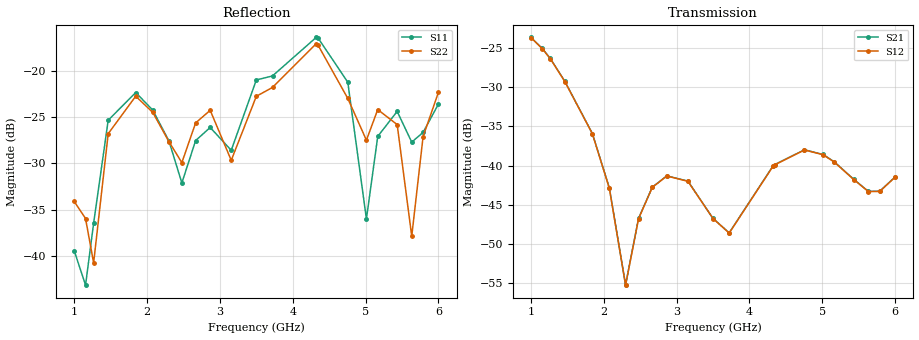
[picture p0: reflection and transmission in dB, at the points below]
!Agilent Technologies,E8364B,MY43040528,A.07.50.67
!Agilent E8364B: A.07.50.67
!Date: Sunday, March 01, 2026 20:46:33
!Correction: S11(Full 2 Port(1,2))
!S21(Full 2 Port(1,2))
!S12(Full 2 Port(1,2))
!S22(Full 2 Port(1,2))
!S2P File: Measurements: S11, S21, S12, S22:
# Hz S  dB  R 50
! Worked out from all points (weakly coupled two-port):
!   451 points, 1 GHz to 6 GHz, reference 50 ohm
!   highest |S21| = -23.64 dB at 1 GHz (marker M1); lowest = -55.2 dB at 2.3 GHz (marker M2)
!   lowest |S11| = -43.1 dB at 1.156 GHz (marker M3), VSWR 1.01, Z = 49.5 + j0.524 ohm
!   |S11| at or under -10 dB: start of sweep to end of sweep
!   |S22| runs from -40.8 to -16.9 dB; largest |S21 - S12| = 0.00017
!   S11 on the Smith chart (normalised r, x): 1 GHz: 1.01, +0.02; 4.322 GHz: 1.24, -0.24; 6 GHz: 0.99, -0.13
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1e9  -39.42 64.4  -23.64 148.8  -23.66 148.7  -34.11 23.5
1.155556e9  -43.13 130.6  -25.05 58.8  -25.07 58.8  -35.95 28.7
1.266667e9  -36.46 -174.9  -26.33 -5.2  -26.36 -5.2  -40.73 73.4
1.466667e9  -25.36 161.9  -29.26 -117.4  -29.28 -117.4  -26.81 84.9
1.844444e9  -22.37 93.8  -35.92 37.9  -35.94 38.0  -22.77 2.2
2.077778e9  -24.26 66.8  -42.87 -85.0  -42.91 -85.1  -24.51 -33.1
2.3e9  -27.58 48.7  -55.22 -131.8  -55.25 -131.8  -27.66 -57.3
2.477778e9  -32.12 65.2  -46.74 -166.5  -46.79 -166.4  -29.93 -47.3
2.666667e9  -27.55 83.0  -42.76 96.5  -42.77 96.5  -25.65 -51.1
2.866667e9  -26.14 57.6  -41.31 -11.2  -41.33 -11.2  -24.29 -89.5
3.155556e9  -28.60 78.0  -41.98 -167.8  -42.00 -167.8  -29.68 -101.8
3.5e9  -21.02 50.5  -46.74 23.4  -46.75 23.3  -22.78 -121.4
3.722222e9  -20.58 31.4  -48.58 -52.5  -48.61 -52.5  -21.82 -144.0
4.322222e9  -16.43 -38.8  -40.07 25.2  -40.11 25.2  -17.11 118.1
4.344444e9  -16.46 -42.2  -39.89 13.1  -39.91 13.1  -17.23 113.6
4.755556e9  -21.26 -110.2  -37.98 139.5  -38.01 139.6  -23.01 38.9
5.011111e9  -36.00 -92.1  -38.58 -12.0  -38.61 -12.0  -27.51 52.0
5.166667e9  -27.10 -49.7  -39.53 -106.2  -39.56 -106.2  -24.21 40.6
5.433333e9  -24.41 -91.1  -41.76 83.5  -41.79 83.5  -25.83 -18.5
5.633333e9  -27.72 -96.8  -43.29 -57.0  -43.31 -57.0  -37.86 5.3
5.788889e9  -26.67 -81.9  -43.26 -170.7  -43.30 -170.6  -27.13 36.4
6e9  -23.62 -90.7  -41.45 42.1  -41.47 42.2  -22.35 -2.7
